###############################################################
#  Generated by:      Cadence Innovus 21.16-s078_1
#  OS:                Linux x86_64(Host ID r7cad-generic)
#  Generated on:      Sun Jun  2 17:44:32 2024
#  Design:            Pathtracer
#  Command:           write_lef_abstract -specifyTopLayer 6 -PGPinLayers {5 6} -noCutObs -stripePin results/Pathtracer.lef
###############################################################

VERSION 5.8 ;

BUSBITCHARS "[]" ;
DIVIDERCHAR "/" ;

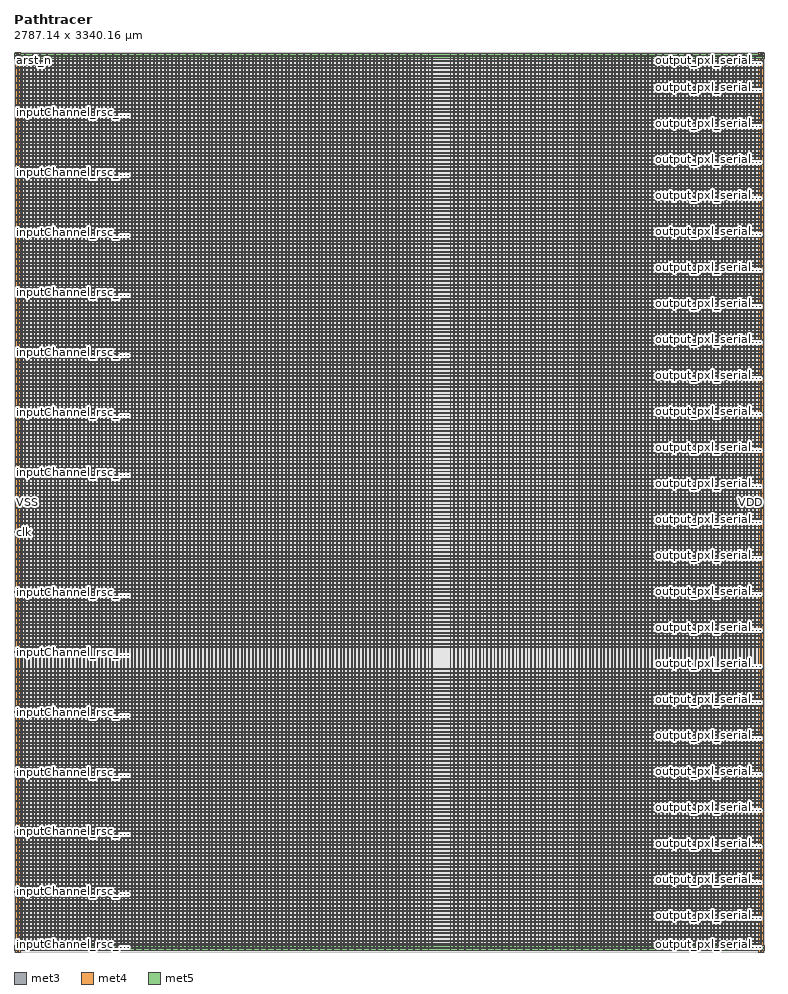
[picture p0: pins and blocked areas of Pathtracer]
MACRO Pathtracer
  CLASS BLOCK ;
  SIZE 2787.140000 BY 3340.160000 ;
  FOREIGN Pathtracer 0.000000 0.000000 ;
  ORIGIN 0 0 ;
  SYMMETRY X Y R90 ;
  PIN clk
    DIRECTION INPUT ;
    USE SIGNAL ;
    ANTENNAPARTIALMETALAREA 8.9964 LAYER met3  ;
    ANTENNAPARTIALMETALSIDEAREA 47.976 LAYER met3  ;
    ANTENNAMODEL OXIDE1 ;
    ANTENNAGATEAREA 0.576 LAYER met3  ;
    ANTENNAMAXAREACAR 17.1122 LAYER met3  ;
    ANTENNAMAXSIDEAREACAR 88.5634 LAYER met3  ;
    ANTENNAMAXCUTCAR 0.158681 LAYER via3  ;
    PORT
      LAYER met3 ;
        RECT 0.000000 1558.460000 0.800000 1558.760000 ;
    END
  END clk
  PIN arst_n
    DIRECTION INPUT ;
    USE SIGNAL ;
    ANTENNAPARTIALMETALAREA 8.8104 LAYER met3  ;
    ANTENNAPARTIALMETALSIDEAREA 46.984 LAYER met3  ;
    ANTENNAMODEL OXIDE1 ;
    ANTENNAGATEAREA 0.495 LAYER met3  ;
    ANTENNAMAXAREACAR 26.7883 LAYER met3  ;
    ANTENNAMAXSIDEAREACAR 138.764 LAYER met3  ;
    ANTENNAMAXCUTCAR 0.184646 LAYER via3  ;
    PORT
      LAYER met3 ;
        RECT 0.000000 3339.660000 0.800000 3339.960000 ;
    END
  END arst_n
  PIN inputChannel_rsc_dat[11]
    DIRECTION INPUT ;
    USE SIGNAL ;
    ANTENNAPARTIALMETALAREA 14.5426 LAYER met3  ;
    ANTENNAPARTIALMETALSIDEAREA 77.552 LAYER met3  ;
    ANTENNAPARTIALCUTAREA 0.04 LAYER via3  ;
    ANTENNAPARTIALMETALAREA 13.5838 LAYER met4  ;
    ANTENNAPARTIALMETALSIDEAREA 68.792 LAYER met4  ;
    ANTENNAPARTIALCUTAREA 0.64 LAYER via4  ;
    ANTENNADIFFAREA 0.4347 LAYER met5  ;
    ANTENNAPARTIALMETALAREA 85.36 LAYER met5  ;
    ANTENNAPARTIALMETALSIDEAREA 131.88 LAYER met5  ;
    ANTENNAMODEL OXIDE1 ;
    ANTENNAGATEAREA 0.2475 LAYER met5  ;
    ANTENNAMAXAREACAR 426.249 LAYER met5  ;
    ANTENNAMAXSIDEAREACAR 940.113 LAYER met5  ;
    PORT
      LAYER met3 ;
        RECT 0.000000 445.210000 0.800000 445.510000 ;
    END
  END inputChannel_rsc_dat[11]
  PIN inputChannel_rsc_dat[10]
    DIRECTION INPUT ;
    USE SIGNAL ;
    ANTENNAPARTIALMETALAREA 25.5874 LAYER met3  ;
    ANTENNAPARTIALMETALSIDEAREA 136.928 LAYER met3  ;
    ANTENNAPARTIALCUTAREA 0.04 LAYER via3  ;
    ANTENNAPARTIALMETALAREA 0.6516 LAYER met4  ;
    ANTENNAPARTIALMETALSIDEAREA 4.416 LAYER met4  ;
    ANTENNAMODEL OXIDE1 ;
    ANTENNAGATEAREA 0.2475 LAYER met4  ;
    ANTENNAMAXAREACAR 21.1174 LAYER met4  ;
    ANTENNAMAXSIDEAREACAR 109.038 LAYER met4  ;
    ANTENNAMAXCUTCAR 0.530909 LAYER via4  ;
    PORT
      LAYER met3 ;
        RECT 0.000000 667.860000 0.800000 668.160000 ;
    END
  END inputChannel_rsc_dat[10]
  PIN inputChannel_rsc_dat[9]
    DIRECTION INPUT ;
    USE SIGNAL ;
    ANTENNAPARTIALMETALAREA 22.3684 LAYER met3  ;
    ANTENNAPARTIALMETALSIDEAREA 119.76 LAYER met3  ;
    ANTENNAPARTIALCUTAREA 0.04 LAYER via3  ;
    ANTENNAPARTIALMETALAREA 0.6516 LAYER met4  ;
    ANTENNAPARTIALMETALSIDEAREA 4.416 LAYER met4  ;
    ANTENNAMODEL OXIDE1 ;
    ANTENNAGATEAREA 0.2475 LAYER met4  ;
    ANTENNAMAXAREACAR 29.9465 LAYER met4  ;
    ANTENNAMAXSIDEAREACAR 152.501 LAYER met4  ;
    ANTENNAMAXCUTCAR 0.530909 LAYER via4  ;
    PORT
      LAYER met3 ;
        RECT 0.000000 890.510000 0.800000 890.810000 ;
    END
  END inputChannel_rsc_dat[9]
  PIN inputChannel_rsc_dat[8]
    DIRECTION INPUT ;
    USE SIGNAL ;
    ANTENNAPARTIALMETALAREA 7.5334 LAYER met3  ;
    ANTENNAPARTIALMETALSIDEAREA 40.64 LAYER met3  ;
    ANTENNAPARTIALCUTAREA 0.04 LAYER via3  ;
    ANTENNAPARTIALMETALAREA 69.7006 LAYER met4  ;
    ANTENNAPARTIALMETALSIDEAREA 368.552 LAYER met4  ;
    ANTENNAPARTIALCUTAREA 0.64 LAYER via4  ;
    ANTENNADIFFAREA 0.4347 LAYER met5  ;
    ANTENNAPARTIALMETALAREA 112.96 LAYER met5  ;
    ANTENNAPARTIALMETALSIDEAREA 173.28 LAYER met5  ;
    ANTENNAMODEL OXIDE1 ;
    ANTENNAGATEAREA 0.2475 LAYER met5  ;
    ANTENNAMAXAREACAR 515.063 LAYER met5  ;
    ANTENNAMAXSIDEAREACAR 989.592 LAYER met5  ;
    PORT
      LAYER met3 ;
        RECT 0.000000 1113.160000 0.800000 1113.460000 ;
    END
  END inputChannel_rsc_dat[8]
  PIN inputChannel_rsc_dat[7]
    DIRECTION INPUT ;
    USE SIGNAL ;
    ANTENNAPARTIALMETALAREA 21.4024 LAYER met3  ;
    ANTENNAPARTIALMETALSIDEAREA 114.608 LAYER met3  ;
    ANTENNAPARTIALCUTAREA 0.04 LAYER via3  ;
    ANTENNAPARTIALMETALAREA 1.1766 LAYER met4  ;
    ANTENNAPARTIALMETALSIDEAREA 7.216 LAYER met4  ;
    ANTENNAMODEL OXIDE1 ;
    ANTENNAGATEAREA 0.2475 LAYER met4  ;
    ANTENNAMAXAREACAR 21.7735 LAYER met4  ;
    ANTENNAMAXSIDEAREACAR 112.036 LAYER met4  ;
    ANTENNAMAXCUTCAR 0.530909 LAYER via4  ;
    PORT
      LAYER met3 ;
        RECT 0.000000 1335.810000 0.800000 1336.110000 ;
    END
  END inputChannel_rsc_dat[7]
  PIN inputChannel_rsc_dat[6]
    DIRECTION INPUT ;
    USE SIGNAL ;
    ANTENNAPARTIALMETALAREA 14.1784 LAYER met3  ;
    ANTENNAPARTIALMETALSIDEAREA 76.08 LAYER met3  ;
    ANTENNAPARTIALCUTAREA 0.04 LAYER via3  ;
    ANTENNAPARTIALMETALAREA 0.6516 LAYER met4  ;
    ANTENNAPARTIALMETALSIDEAREA 4.416 LAYER met4  ;
    ANTENNAMODEL OXIDE1 ;
    ANTENNAGATEAREA 0.2475 LAYER met4  ;
    ANTENNAMAXAREACAR 50.3853 LAYER met4  ;
    ANTENNAMAXSIDEAREACAR 264.857 LAYER met4  ;
    ANTENNAMAXCUTCAR 0.530909 LAYER via4  ;
    PORT
      LAYER met3 ;
        RECT 0.000000 1781.110000 0.800000 1781.410000 ;
    END
  END inputChannel_rsc_dat[6]
  PIN inputChannel_rsc_dat[5]
    DIRECTION INPUT ;
    USE SIGNAL ;
    ANTENNAPARTIALMETALAREA 0.6954 LAYER met3  ;
    ANTENNAPARTIALMETALSIDEAREA 4.152 LAYER met3  ;
    ANTENNAPARTIALCUTAREA 0.04 LAYER via3  ;
    ANTENNAPARTIALMETALAREA 6.1578 LAYER met4  ;
    ANTENNAPARTIALMETALSIDEAREA 33.312 LAYER met4  ;
    ANTENNAMODEL OXIDE1 ;
    ANTENNAGATEAREA 0.1965 LAYER met4  ;
    ANTENNAMAXAREACAR 55.7527 LAYER met4  ;
    ANTENNAMAXSIDEAREACAR 290.656 LAYER met4  ;
    ANTENNAMAXCUTCAR 0.668702 LAYER via4  ;
    PORT
      LAYER met3 ;
        RECT 0.000000 2003.760000 0.800000 2004.060000 ;
    END
  END inputChannel_rsc_dat[5]
  PIN inputChannel_rsc_dat[4]
    DIRECTION INPUT ;
    USE SIGNAL ;
    ANTENNAPARTIALMETALAREA 6.3744 LAYER met3  ;
    ANTENNAPARTIALMETALSIDEAREA 33.992 LAYER met3  ;
    ANTENNAMODEL OXIDE1 ;
    ANTENNAGATEAREA 1.33 LAYER met3  ;
    ANTENNAMAXAREACAR 10.6479 LAYER met3  ;
    ANTENNAMAXSIDEAREACAR 54.0436 LAYER met3  ;
    ANTENNAMAXCUTCAR 0.0687218 LAYER via3  ;
    PORT
      LAYER met3 ;
        RECT 0.000000 2226.410000 0.800000 2226.710000 ;
    END
  END inputChannel_rsc_dat[4]
  PIN inputChannel_rsc_dat[3]
    DIRECTION INPUT ;
    USE SIGNAL ;
    ANTENNAPARTIALMETALAREA 8.3064 LAYER met3  ;
    ANTENNAPARTIALMETALSIDEAREA 44.296 LAYER met3  ;
    ANTENNAMODEL OXIDE1 ;
    ANTENNAGATEAREA 1.33 LAYER met3  ;
    ANTENNAMAXAREACAR 12.5679 LAYER met3  ;
    ANTENNAMAXSIDEAREACAR 64.1278 LAYER met3  ;
    ANTENNAMAXCUTCAR 0.0687218 LAYER via3  ;
    PORT
      LAYER met3 ;
        RECT 0.000000 2449.060000 0.800000 2449.360000 ;
    END
  END inputChannel_rsc_dat[3]
  PIN inputChannel_rsc_dat[2]
    DIRECTION INPUT ;
    USE SIGNAL ;
    ANTENNAPARTIALMETALAREA 0.467025 LAYER met3  ;
    ANTENNAPARTIALMETALSIDEAREA 2.464 LAYER met3  ;
    ANTENNAMODEL OXIDE1 ;
    ANTENNAGATEAREA 0.2475 LAYER met3  ;
    ANTENNAMAXAREACAR 98.466 LAYER met3  ;
    ANTENNAMAXSIDEAREACAR 490.628 LAYER met3  ;
    ANTENNAMAXCUTCAR 0.369293 LAYER via3  ;
    PORT
      LAYER met3 ;
        RECT 0.000000 2671.710000 0.800000 2672.010000 ;
    END
  END inputChannel_rsc_dat[2]
  PIN inputChannel_rsc_dat[1]
    DIRECTION INPUT ;
    USE SIGNAL ;
    ANTENNAPARTIALMETALAREA 0.4404 LAYER met3  ;
    ANTENNAPARTIALMETALSIDEAREA 2.344 LAYER met3  ;
    ANTENNAMODEL OXIDE1 ;
    ANTENNAGATEAREA 1.98 LAYER met3  ;
    ANTENNAMAXAREACAR 2.77518 LAYER met3  ;
    ANTENNAMAXSIDEAREACAR 12.3333 LAYER met3  ;
    ANTENNAMAXCUTCAR 0.0461616 LAYER via3  ;
    PORT
      LAYER met3 ;
        RECT 0.000000 2894.360000 0.800000 2894.660000 ;
    END
  END inputChannel_rsc_dat[1]
  PIN inputChannel_rsc_dat[0]
    DIRECTION INPUT ;
    USE SIGNAL ;
    ANTENNAPARTIALMETALAREA 0.1644 LAYER met3  ;
    ANTENNAPARTIALMETALSIDEAREA 0.872 LAYER met3  ;
    ANTENNAMODEL OXIDE1 ;
    ANTENNAGATEAREA 0.99 LAYER met3  ;
    ANTENNAMAXAREACAR 4.78626 LAYER met3  ;
    ANTENNAMAXSIDEAREACAR 22.098 LAYER met3  ;
    ANTENNAMAXCUTCAR 0.0923232 LAYER via3  ;
    PORT
      LAYER met3 ;
        RECT 0.000000 3117.010000 0.800000 3117.310000 ;
    END
  END inputChannel_rsc_dat[0]
  PIN inputChannel_rsc_vld
    DIRECTION INPUT ;
    USE SIGNAL ;
    ANTENNAPARTIALMETALAREA 4.1664 LAYER met3  ;
    ANTENNAPARTIALMETALSIDEAREA 22.216 LAYER met3  ;
    ANTENNAMODEL OXIDE1 ;
    ANTENNAGATEAREA 0.495 LAYER met3  ;
    ANTENNAMAXAREACAR 13.9792 LAYER met3  ;
    ANTENNAMAXSIDEAREACAR 70.4586 LAYER met3  ;
    ANTENNAMAXCUTCAR 0.184646 LAYER via3  ;
    PORT
      LAYER met3 ;
        RECT 0.000000 222.560000 0.800000 222.860000 ;
    END
  END inputChannel_rsc_vld
  PIN inputChannel_rsc_rdy
    DIRECTION OUTPUT ;
    USE SIGNAL ;
    ANTENNAPARTIALMETALAREA 104.747 LAYER met3  ;
    ANTENNAPARTIALMETALSIDEAREA 558.64 LAYER met3  ;
    ANTENNAPARTIALCUTAREA 0.04 LAYER via3  ;
    ANTENNAPARTIALMETALAREA 125.015 LAYER met4  ;
    ANTENNAPARTIALMETALSIDEAREA 664.504 LAYER met4  ;
    ANTENNAPARTIALCUTAREA 0.64 LAYER via4  ;
    ANTENNADIFFAREA 0.4455 LAYER met5  ;
    ANTENNAPARTIALMETALAREA 7.44 LAYER met5  ;
    ANTENNAPARTIALMETALSIDEAREA 15 LAYER met5  ;
    ANTENNAMODEL OXIDE1 ;
    ANTENNAGATEAREA 0.126 LAYER met5  ;
    ANTENNAMAXAREACAR 363.937 LAYER met5  ;
    ANTENNAMAXSIDEAREACAR 1706.82 LAYER met5  ;
    PORT
      LAYER met3 ;
        RECT 0.000000 0.520000 0.800000 0.820000 ;
    END
  END inputChannel_rsc_rdy
  PIN output_pxl_serial_rsc_dat[23]
    DIRECTION OUTPUT ;
    USE SIGNAL ;
    ANTENNADIFFAREA 0.4455 LAYER met3  ;
    ANTENNAPARTIALMETALAREA 0.2844 LAYER met3  ;
    ANTENNAPARTIALMETALSIDEAREA 1.992 LAYER met3  ;
    PORT
      LAYER met3 ;
        RECT 2786.340000 267.700000 2787.140000 268.000000 ;
    END
  END output_pxl_serial_rsc_dat[23]
  PIN output_pxl_serial_rsc_dat[22]
    DIRECTION OUTPUT ;
    USE SIGNAL ;
    ANTENNADIFFAREA 0.4455 LAYER met3  ;
    ANTENNAPARTIALMETALAREA 0.4224 LAYER met3  ;
    ANTENNAPARTIALMETALSIDEAREA 2.728 LAYER met3  ;
    PORT
      LAYER met3 ;
        RECT 2786.340000 401.290000 2787.140000 401.590000 ;
    END
  END output_pxl_serial_rsc_dat[22]
  PIN output_pxl_serial_rsc_dat[21]
    DIRECTION OUTPUT ;
    USE SIGNAL ;
    ANTENNAPARTIALMETALAREA 4.3786 LAYER met3  ;
    ANTENNAPARTIALMETALSIDEAREA 23.344 LAYER met3  ;
    ANTENNAPARTIALCUTAREA 0.04 LAYER via3  ;
    ANTENNADIFFAREA 0.4455 LAYER met4  ;
    ANTENNAPARTIALMETALAREA 18.0528 LAYER met4  ;
    ANTENNAPARTIALMETALSIDEAREA 96.752 LAYER met4  ;
    PORT
      LAYER met3 ;
        RECT 2786.340000 534.880000 2787.140000 535.180000 ;
    END
  END output_pxl_serial_rsc_dat[21]
  PIN output_pxl_serial_rsc_dat[20]
    DIRECTION OUTPUT ;
    USE SIGNAL ;
    ANTENNAPARTIALMETALAREA 0.2386 LAYER met3  ;
    ANTENNAPARTIALMETALSIDEAREA 1.264 LAYER met3  ;
    ANTENNAPARTIALCUTAREA 0.04 LAYER via3  ;
    ANTENNADIFFAREA 0.4455 LAYER met4  ;
    ANTENNAPARTIALMETALAREA 57.9468 LAYER met4  ;
    ANTENNAPARTIALMETALSIDEAREA 309.52 LAYER met4  ;
    PORT
      LAYER met3 ;
        RECT 2786.340000 668.470000 2787.140000 668.770000 ;
    END
  END output_pxl_serial_rsc_dat[20]
  PIN output_pxl_serial_rsc_dat[19]
    DIRECTION OUTPUT ;
    USE SIGNAL ;
    ANTENNADIFFAREA 0.4455 LAYER met3  ;
    ANTENNAPARTIALMETALAREA 2.3544 LAYER met3  ;
    ANTENNAPARTIALMETALSIDEAREA 13.032 LAYER met3  ;
    PORT
      LAYER met3 ;
        RECT 2786.340000 802.060000 2787.140000 802.360000 ;
    END
  END output_pxl_serial_rsc_dat[19]
  PIN output_pxl_serial_rsc_dat[18]
    DIRECTION OUTPUT ;
    USE SIGNAL ;
    ANTENNADIFFAREA 0.4455 LAYER met3  ;
    ANTENNAPARTIALMETALAREA 13.7892 LAYER met3  ;
    ANTENNAPARTIALMETALSIDEAREA 74.488 LAYER met3  ;
    PORT
      LAYER met3 ;
        RECT 2786.340000 935.650000 2787.140000 935.950000 ;
    END
  END output_pxl_serial_rsc_dat[18]
  PIN output_pxl_serial_rsc_dat[17]
    DIRECTION OUTPUT ;
    USE SIGNAL ;
    ANTENNADIFFAREA 0.4455 LAYER met3  ;
    ANTENNAPARTIALMETALAREA 1.6644 LAYER met3  ;
    ANTENNAPARTIALMETALSIDEAREA 9.352 LAYER met3  ;
    PORT
      LAYER met3 ;
        RECT 2786.340000 1069.240000 2787.140000 1069.540000 ;
    END
  END output_pxl_serial_rsc_dat[17]
  PIN output_pxl_serial_rsc_dat[16]
    DIRECTION OUTPUT ;
    USE SIGNAL ;
    ANTENNADIFFAREA 0.4455 LAYER met3  ;
    ANTENNAPARTIALMETALAREA 13.0992 LAYER met3  ;
    ANTENNAPARTIALMETALSIDEAREA 70.808 LAYER met3  ;
    PORT
      LAYER met3 ;
        RECT 2786.340000 1202.830000 2787.140000 1203.130000 ;
    END
  END output_pxl_serial_rsc_dat[16]
  PIN output_pxl_serial_rsc_dat[15]
    DIRECTION OUTPUT ;
    USE SIGNAL ;
    ANTENNADIFFAREA 0.4455 LAYER met3  ;
    ANTENNAPARTIALMETALAREA 1.5264 LAYER met3  ;
    ANTENNAPARTIALMETALSIDEAREA 8.616 LAYER met3  ;
    PORT
      LAYER met3 ;
        RECT 2786.340000 1336.420000 2787.140000 1336.720000 ;
    END
  END output_pxl_serial_rsc_dat[15]
  PIN output_pxl_serial_rsc_dat[14]
    DIRECTION OUTPUT ;
    USE SIGNAL ;
    ANTENNADIFFAREA 0.4455 LAYER met3  ;
    ANTENNAPARTIALMETALAREA 0.5604 LAYER met3  ;
    ANTENNAPARTIALMETALSIDEAREA 3.464 LAYER met3  ;
    PORT
      LAYER met3 ;
        RECT 2786.340000 1470.010000 2787.140000 1470.310000 ;
    END
  END output_pxl_serial_rsc_dat[14]
  PIN output_pxl_serial_rsc_dat[13]
    DIRECTION OUTPUT ;
    USE SIGNAL ;
    ANTENNADIFFAREA 0.4455 LAYER met3  ;
    ANTENNAPARTIALMETALAREA 0.5604 LAYER met3  ;
    ANTENNAPARTIALMETALSIDEAREA 3.464 LAYER met3  ;
    PORT
      LAYER met3 ;
        RECT 2786.340000 1603.600000 2787.140000 1603.900000 ;
    END
  END output_pxl_serial_rsc_dat[13]
  PIN output_pxl_serial_rsc_dat[12]
    DIRECTION OUTPUT ;
    USE SIGNAL ;
    ANTENNADIFFAREA 0.43675 LAYER met3  ;
    ANTENNAPARTIALMETALAREA 0.3024 LAYER met3  ;
    ANTENNAPARTIALMETALSIDEAREA 1.608 LAYER met3  ;
    PORT
      LAYER met3 ;
        RECT 2786.340000 1737.190000 2787.140000 1737.490000 ;
    END
  END output_pxl_serial_rsc_dat[12]
  PIN output_pxl_serial_rsc_dat[11]
    DIRECTION OUTPUT ;
    USE SIGNAL ;
    ANTENNADIFFAREA 0.43675 LAYER met3  ;
    ANTENNAPARTIALMETALAREA 0.6492 LAYER met3  ;
    ANTENNAPARTIALMETALSIDEAREA 3.928 LAYER met3  ;
    PORT
      LAYER met3 ;
        RECT 2786.340000 1870.780000 2787.140000 1871.080000 ;
    END
  END output_pxl_serial_rsc_dat[11]
  PIN output_pxl_serial_rsc_dat[10]
    DIRECTION OUTPUT ;
    USE SIGNAL ;
    ANTENNADIFFAREA 0.43675 LAYER met3  ;
    ANTENNAPARTIALMETALAREA 5.9604 LAYER met3  ;
    ANTENNAPARTIALMETALSIDEAREA 31.784 LAYER met3  ;
    PORT
      LAYER met3 ;
        RECT 2786.340000 2004.370000 2787.140000 2004.670000 ;
    END
  END output_pxl_serial_rsc_dat[10]
  PIN output_pxl_serial_rsc_dat[9]
    DIRECTION OUTPUT ;
    USE SIGNAL ;
    ANTENNADIFFAREA 0.43675 LAYER met3  ;
    ANTENNAPARTIALMETALAREA 0.7164 LAYER met3  ;
    ANTENNAPARTIALMETALSIDEAREA 3.816 LAYER met3  ;
    PORT
      LAYER met3 ;
        RECT 2786.340000 2137.960000 2787.140000 2138.260000 ;
    END
  END output_pxl_serial_rsc_dat[9]
  PIN output_pxl_serial_rsc_dat[8]
    DIRECTION OUTPUT ;
    USE SIGNAL ;
    ANTENNADIFFAREA 0.714 LAYER met3  ;
    ANTENNAPARTIALMETALAREA 0.7164 LAYER met3  ;
    ANTENNAPARTIALMETALSIDEAREA 3.816 LAYER met3  ;
    PORT
      LAYER met3 ;
        RECT 2786.340000 2271.550000 2787.140000 2271.850000 ;
    END
  END output_pxl_serial_rsc_dat[8]
  PIN output_pxl_serial_rsc_dat[7]
    DIRECTION OUTPUT ;
    USE SIGNAL ;
    ANTENNADIFFAREA 0.714 LAYER met3  ;
    ANTENNAPARTIALMETALAREA 0.4404 LAYER met3  ;
    ANTENNAPARTIALMETALSIDEAREA 2.344 LAYER met3  ;
    PORT
      LAYER met3 ;
        RECT 2786.340000 2405.140000 2787.140000 2405.440000 ;
    END
  END output_pxl_serial_rsc_dat[7]
  PIN output_pxl_serial_rsc_dat[6]
    DIRECTION OUTPUT ;
    USE SIGNAL ;
    ANTENNADIFFAREA 0.714 LAYER met3  ;
    ANTENNAPARTIALMETALAREA 0.8544 LAYER met3  ;
    ANTENNAPARTIALMETALSIDEAREA 4.552 LAYER met3  ;
    PORT
      LAYER met3 ;
        RECT 2786.340000 2538.730000 2787.140000 2539.030000 ;
    END
  END output_pxl_serial_rsc_dat[6]
  PIN output_pxl_serial_rsc_dat[5]
    DIRECTION OUTPUT ;
    USE SIGNAL ;
    ANTENNADIFFAREA 0.714 LAYER met3  ;
    ANTENNAPARTIALMETALAREA 0.1644 LAYER met3  ;
    ANTENNAPARTIALMETALSIDEAREA 0.872 LAYER met3  ;
    PORT
      LAYER met3 ;
        RECT 2786.340000 2672.320000 2787.140000 2672.620000 ;
    END
  END output_pxl_serial_rsc_dat[5]
  PIN output_pxl_serial_rsc_dat[4]
    DIRECTION OUTPUT ;
    USE SIGNAL ;
    ANTENNADIFFAREA 0.43675 LAYER met3  ;
    ANTENNAPARTIALMETALAREA 0.8544 LAYER met3  ;
    ANTENNAPARTIALMETALSIDEAREA 4.552 LAYER met3  ;
    PORT
      LAYER met3 ;
        RECT 2786.340000 2805.910000 2787.140000 2806.210000 ;
    END
  END output_pxl_serial_rsc_dat[4]
  PIN output_pxl_serial_rsc_dat[3]
    DIRECTION OUTPUT ;
    USE SIGNAL ;
    ANTENNADIFFAREA 0.714 LAYER met3  ;
    ANTENNAPARTIALMETALAREA 0.1644 LAYER met3  ;
    ANTENNAPARTIALMETALSIDEAREA 0.872 LAYER met3  ;
    PORT
      LAYER met3 ;
        RECT 2786.340000 2939.500000 2787.140000 2939.800000 ;
    END
  END output_pxl_serial_rsc_dat[3]
  PIN output_pxl_serial_rsc_dat[2]
    DIRECTION OUTPUT ;
    USE SIGNAL ;
    ANTENNADIFFAREA 0.714 LAYER met3  ;
    ANTENNAPARTIALMETALAREA 0.9924 LAYER met3  ;
    ANTENNAPARTIALMETALSIDEAREA 5.288 LAYER met3  ;
    PORT
      LAYER met3 ;
        RECT 2786.340000 3073.090000 2787.140000 3073.390000 ;
    END
  END output_pxl_serial_rsc_dat[2]
  PIN output_pxl_serial_rsc_dat[1]
    DIRECTION OUTPUT ;
    USE SIGNAL ;
    ANTENNADIFFAREA 0.714 LAYER met3  ;
    ANTENNAPARTIALMETALAREA 1.9584 LAYER met3  ;
    ANTENNAPARTIALMETALSIDEAREA 10.44 LAYER met3  ;
    PORT
      LAYER met3 ;
        RECT 2786.340000 3206.680000 2787.140000 3206.980000 ;
    END
  END output_pxl_serial_rsc_dat[1]
  PIN output_pxl_serial_rsc_dat[0]
    DIRECTION OUTPUT ;
    USE SIGNAL ;
    ANTENNADIFFAREA 0.43675 LAYER met3  ;
    ANTENNAPARTIALMETALAREA 0.8064 LAYER met3  ;
    ANTENNAPARTIALMETALSIDEAREA 4.296 LAYER met3  ;
    PORT
      LAYER met3 ;
        RECT 2786.340000 3339.660000 2787.140000 3339.960000 ;
    END
  END output_pxl_serial_rsc_dat[0]
  PIN output_pxl_serial_rsc_vld
    DIRECTION OUTPUT ;
    USE SIGNAL ;
    ANTENNADIFFAREA 0.4355 LAYER met3  ;
    ANTENNAPARTIALMETALAREA 7.7364 LAYER met3  ;
    ANTENNAPARTIALMETALSIDEAREA 41.736 LAYER met3  ;
    ANTENNAMODEL OXIDE1 ;
    ANTENNAGATEAREA 0.126 LAYER met3  ;
    ANTENNAMAXAREACAR 226.856 LAYER met3  ;
    ANTENNAMAXSIDEAREACAR 1145.98 LAYER met3  ;
    ANTENNAMAXCUTCAR 0.903968 LAYER via3  ;
    PORT
      LAYER met3 ;
        RECT 2786.340000 134.110000 2787.140000 134.410000 ;
    END
  END output_pxl_serial_rsc_vld
  PIN output_pxl_serial_rsc_rdy
    DIRECTION INPUT ;
    USE SIGNAL ;
    ANTENNAPARTIALMETALAREA 1.662 LAYER met3  ;
    ANTENNAPARTIALMETALSIDEAREA 10.28 LAYER met3  ;
    ANTENNAMODEL OXIDE1 ;
    ANTENNAGATEAREA 0.126 LAYER met3  ;
    ANTENNAMAXAREACAR 66.9472 LAYER met3  ;
    ANTENNAMAXSIDEAREACAR 342.766 LAYER met3  ;
    ANTENNAMAXCUTCAR 0.725397 LAYER via3  ;
    PORT
      LAYER met3 ;
        RECT 2786.340000 0.520000 2787.140000 0.820000 ;
    END
  END output_pxl_serial_rsc_rdy
  PIN VSS
    DIRECTION INOUT ;
    USE GROUND ;
    PORT
      LAYER met4 ;
        RECT 2774.480000 3332.000000 2782.640000 3340.160000 ;
    END
    PORT
      LAYER met4 ;
        RECT 2774.480000 0.000000 2782.640000 8.160000 ;
    END
    PORT
      LAYER met4 ;
        RECT 4.500000 3332.000000 12.660000 3340.160000 ;
    END
    PORT
      LAYER met4 ;
        RECT 4.500000 0.000000 12.660000 8.160000 ;
    END
    PORT
      LAYER met5 ;
        RECT 2778.980000 3327.920000 2787.140000 3336.080000 ;
    END
    PORT
      LAYER met5 ;
        RECT 0.000000 3327.920000 8.160000 3336.080000 ;
    END
    PORT
      LAYER met5 ;
        RECT 2778.980000 4.080000 2787.140000 12.240000 ;
    END
    PORT
      LAYER met5 ;
        RECT 0.000000 4.080000 8.160000 12.240000 ;
    END

# P/G power stripe data as pin
    PORT
      LAYER met4 ;
        RECT 40.800000 4.080000 44.160000 3336.080000 ;
        RECT 2774.480000 0.000000 2782.640000 3340.160000 ;
        RECT 4.500000 0.000000 12.660000 3340.160000 ;
        RECT 1618.400000 4.080000 1621.760000 3336.080000 ;
        RECT 68.000000 4.080000 71.360000 3336.080000 ;
        RECT 95.200000 4.080000 98.560000 3336.080000 ;
        RECT 122.400000 4.080000 125.760000 3336.080000 ;
        RECT 149.600000 4.080000 152.960000 3336.080000 ;
        RECT 176.800000 4.080000 180.160000 3336.080000 ;
        RECT 204.000000 4.080000 207.360000 3336.080000 ;
        RECT 231.200000 4.080000 234.560000 3336.080000 ;
        RECT 258.400000 4.080000 261.760000 3336.080000 ;
        RECT 285.600000 4.080000 288.960000 3336.080000 ;
        RECT 312.800000 4.080000 316.160000 3336.080000 ;
        RECT 340.000000 4.080000 343.360000 3336.080000 ;
        RECT 367.200000 4.080000 370.560000 3336.080000 ;
        RECT 394.400000 4.080000 397.760000 3336.080000 ;
        RECT 421.600000 4.080000 424.960000 3336.080000 ;
        RECT 448.800000 4.080000 452.160000 3336.080000 ;
        RECT 476.000000 4.080000 479.360000 3336.080000 ;
        RECT 503.200000 4.080000 506.560000 3336.080000 ;
        RECT 530.400000 4.080000 533.760000 3336.080000 ;
        RECT 557.600000 4.080000 560.960000 3336.080000 ;
        RECT 584.800000 4.080000 588.160000 3336.080000 ;
        RECT 612.000000 4.080000 615.360000 3336.080000 ;
        RECT 639.200000 4.080000 642.560000 3336.080000 ;
        RECT 666.400000 4.080000 669.760000 3336.080000 ;
        RECT 693.600000 4.080000 696.960000 3336.080000 ;
        RECT 720.800000 4.080000 724.160000 3336.080000 ;
        RECT 748.000000 4.080000 751.360000 3336.080000 ;
        RECT 775.200000 4.080000 778.560000 3336.080000 ;
        RECT 802.400000 4.080000 805.760000 3336.080000 ;
        RECT 829.600000 4.080000 832.960000 3336.080000 ;
        RECT 856.800000 4.080000 860.160000 3336.080000 ;
        RECT 884.000000 4.080000 887.360000 3336.080000 ;
        RECT 911.200000 4.080000 914.560000 3336.080000 ;
        RECT 938.400000 4.080000 941.760000 3336.080000 ;
        RECT 965.600000 4.080000 968.960000 3336.080000 ;
        RECT 992.800000 4.080000 996.160000 3336.080000 ;
        RECT 1020.000000 4.080000 1023.360000 3336.080000 ;
        RECT 1047.200000 4.080000 1050.560000 3336.080000 ;
        RECT 1074.400000 4.080000 1077.760000 3336.080000 ;
        RECT 1101.600000 4.080000 1104.960000 3336.080000 ;
        RECT 1128.800000 4.080000 1132.160000 3336.080000 ;
        RECT 1156.000000 4.080000 1159.360000 3336.080000 ;
        RECT 1183.200000 4.080000 1186.560000 3336.080000 ;
        RECT 1210.400000 4.080000 1213.760000 3336.080000 ;
        RECT 1237.600000 4.080000 1240.960000 3336.080000 ;
        RECT 1264.800000 4.080000 1268.160000 3336.080000 ;
        RECT 1292.000000 4.080000 1295.360000 3336.080000 ;
        RECT 1319.200000 4.080000 1322.560000 3336.080000 ;
        RECT 1346.400000 4.080000 1349.760000 3336.080000 ;
        RECT 1373.600000 4.080000 1376.960000 3336.080000 ;
        RECT 1400.800000 4.080000 1404.160000 3336.080000 ;
        RECT 1428.000000 4.080000 1431.360000 3336.080000 ;
        RECT 1455.200000 4.080000 1458.560000 3336.080000 ;
        RECT 1482.400000 4.080000 1485.760000 3336.080000 ;
        RECT 1509.600000 4.080000 1512.960000 3336.080000 ;
        RECT 1536.800000 4.080000 1540.160000 3336.080000 ;
        RECT 1645.600000 4.080000 1648.960000 3336.080000 ;
        RECT 1672.800000 4.080000 1676.160000 3336.080000 ;
        RECT 1700.000000 4.080000 1703.360000 3336.080000 ;
        RECT 1727.200000 4.080000 1730.560000 3336.080000 ;
        RECT 1754.400000 4.080000 1757.760000 3336.080000 ;
        RECT 1781.600000 4.080000 1784.960000 3336.080000 ;
        RECT 1808.800000 4.080000 1812.160000 3336.080000 ;
        RECT 1836.000000 4.080000 1839.360000 3336.080000 ;
        RECT 1863.200000 4.080000 1866.560000 3336.080000 ;
        RECT 1890.400000 4.080000 1893.760000 3336.080000 ;
        RECT 1917.600000 4.080000 1920.960000 3336.080000 ;
        RECT 1944.800000 4.080000 1948.160000 3336.080000 ;
        RECT 1972.000000 4.080000 1975.360000 3336.080000 ;
        RECT 1999.200000 4.080000 2002.560000 3336.080000 ;
        RECT 2026.400000 4.080000 2029.760000 3336.080000 ;
        RECT 2053.600000 4.080000 2056.960000 3336.080000 ;
        RECT 2080.800000 4.080000 2084.160000 3336.080000 ;
        RECT 2108.000000 4.080000 2111.360000 3336.080000 ;
        RECT 2135.200000 4.080000 2138.560000 3336.080000 ;
        RECT 2162.400000 4.080000 2165.760000 3336.080000 ;
        RECT 2189.600000 4.080000 2192.960000 3336.080000 ;
        RECT 2216.800000 4.080000 2220.160000 3336.080000 ;
        RECT 2244.000000 4.080000 2247.360000 3336.080000 ;
        RECT 2271.200000 4.080000 2274.560000 3336.080000 ;
        RECT 2298.400000 4.080000 2301.760000 3336.080000 ;
        RECT 2325.600000 4.080000 2328.960000 3336.080000 ;
        RECT 2352.800000 4.080000 2356.160000 3336.080000 ;
        RECT 2380.000000 4.080000 2383.360000 3336.080000 ;
        RECT 2407.200000 4.080000 2410.560000 3336.080000 ;
        RECT 2434.400000 4.080000 2437.760000 3336.080000 ;
        RECT 2461.600000 4.080000 2464.960000 3336.080000 ;
        RECT 2488.800000 4.080000 2492.160000 3336.080000 ;
        RECT 2516.000000 4.080000 2519.360000 3336.080000 ;
        RECT 2543.200000 4.080000 2546.560000 3336.080000 ;
        RECT 2570.400000 4.080000 2573.760000 3336.080000 ;
        RECT 2597.600000 4.080000 2600.960000 3336.080000 ;
        RECT 2624.800000 4.080000 2628.160000 3336.080000 ;
        RECT 2652.000000 4.080000 2655.360000 3336.080000 ;
        RECT 2679.200000 4.080000 2682.560000 3336.080000 ;
        RECT 2706.400000 4.080000 2709.760000 3336.080000 ;
        RECT 2733.600000 4.080000 2736.960000 3336.080000 ;
      LAYER met5 ;
        RECT 0.000000 4.080000 2787.140000 12.240000 ;
        RECT 4.500000 40.800000 2782.640000 44.160000 ;
        RECT 0.000000 3327.920000 2787.140000 3336.080000 ;
        RECT 4.500000 1128.800000 2782.640000 1132.160000 ;
        RECT 4.500000 1156.000000 2782.640000 1159.360000 ;
        RECT 4.500000 1183.200000 2782.640000 1186.560000 ;
        RECT 4.500000 1210.400000 2782.640000 1213.760000 ;
        RECT 4.500000 1237.600000 2782.640000 1240.960000 ;
        RECT 4.500000 1264.800000 2782.640000 1268.160000 ;
        RECT 4.500000 1292.000000 2782.640000 1295.360000 ;
        RECT 4.500000 1319.200000 2782.640000 1322.560000 ;
        RECT 4.500000 1346.400000 2782.640000 1349.760000 ;
        RECT 4.500000 1373.600000 2782.640000 1376.960000 ;
        RECT 4.500000 1400.800000 2782.640000 1404.160000 ;
        RECT 4.500000 1428.000000 2782.640000 1431.360000 ;
        RECT 4.500000 1455.200000 2782.640000 1458.560000 ;
        RECT 4.500000 1482.400000 2782.640000 1485.760000 ;
        RECT 4.500000 1509.600000 2782.640000 1512.960000 ;
        RECT 4.500000 1536.800000 2782.640000 1540.160000 ;
        RECT 4.500000 1564.000000 2782.640000 1567.360000 ;
        RECT 4.500000 1591.200000 2782.640000 1594.560000 ;
        RECT 4.500000 1618.400000 2782.640000 1621.760000 ;
        RECT 4.500000 1645.600000 2782.640000 1648.960000 ;
        RECT 4.500000 1672.800000 2782.640000 1676.160000 ;
        RECT 4.500000 1700.000000 2782.640000 1703.360000 ;
        RECT 4.500000 1727.200000 2782.640000 1730.560000 ;
        RECT 4.500000 1754.400000 2782.640000 1757.760000 ;
        RECT 4.500000 1781.600000 2782.640000 1784.960000 ;
        RECT 4.500000 1808.800000 2782.640000 1812.160000 ;
        RECT 4.500000 1836.000000 2782.640000 1839.360000 ;
        RECT 4.500000 1863.200000 2782.640000 1866.560000 ;
        RECT 4.500000 1890.400000 2782.640000 1893.760000 ;
        RECT 4.500000 1917.600000 2782.640000 1920.960000 ;
        RECT 4.500000 1944.800000 2782.640000 1948.160000 ;
        RECT 4.500000 1972.000000 2782.640000 1975.360000 ;
        RECT 4.500000 1999.200000 2782.640000 2002.560000 ;
        RECT 4.500000 2026.400000 2782.640000 2029.760000 ;
        RECT 4.500000 2053.600000 2782.640000 2056.960000 ;
        RECT 4.500000 2080.800000 2782.640000 2084.160000 ;
        RECT 4.500000 2108.000000 2782.640000 2111.360000 ;
        RECT 4.500000 2135.200000 2782.640000 2138.560000 ;
        RECT 4.500000 2162.400000 2782.640000 2165.760000 ;
        RECT 4.500000 2189.600000 2782.640000 2192.960000 ;
        RECT 4.500000 2216.800000 2782.640000 2220.160000 ;
        RECT 4.500000 2244.000000 2782.640000 2247.360000 ;
        RECT 4.500000 2271.200000 2782.640000 2274.560000 ;
        RECT 4.500000 2298.400000 2782.640000 2301.760000 ;
        RECT 4.500000 2325.600000 2782.640000 2328.960000 ;
        RECT 4.500000 2352.800000 2782.640000 2356.160000 ;
        RECT 4.500000 2380.000000 2782.640000 2383.360000 ;
        RECT 4.500000 2407.200000 2782.640000 2410.560000 ;
        RECT 4.500000 2434.400000 2782.640000 2437.760000 ;
        RECT 4.500000 2461.600000 2782.640000 2464.960000 ;
        RECT 4.500000 2488.800000 2782.640000 2492.160000 ;
        RECT 4.500000 2516.000000 2782.640000 2519.360000 ;
        RECT 4.500000 2543.200000 2782.640000 2546.560000 ;
        RECT 4.500000 2570.400000 2782.640000 2573.760000 ;
        RECT 4.500000 2597.600000 2782.640000 2600.960000 ;
        RECT 4.500000 2624.800000 2782.640000 2628.160000 ;
        RECT 4.500000 2652.000000 2782.640000 2655.360000 ;
        RECT 4.500000 2679.200000 2782.640000 2682.560000 ;
        RECT 4.500000 2706.400000 2782.640000 2709.760000 ;
        RECT 4.500000 2733.600000 2782.640000 2736.960000 ;
        RECT 4.500000 2760.800000 2782.640000 2764.160000 ;
        RECT 4.500000 2788.000000 2782.640000 2791.360000 ;
        RECT 4.500000 2815.200000 2782.640000 2818.560000 ;
        RECT 4.500000 2842.400000 2782.640000 2845.760000 ;
        RECT 4.500000 2869.600000 2782.640000 2872.960000 ;
        RECT 4.500000 2896.800000 2782.640000 2900.160000 ;
        RECT 4.500000 2924.000000 2782.640000 2927.360000 ;
        RECT 4.500000 2951.200000 2782.640000 2954.560000 ;
        RECT 4.500000 2978.400000 2782.640000 2981.760000 ;
        RECT 4.500000 3005.600000 2782.640000 3008.960000 ;
        RECT 4.500000 3032.800000 2782.640000 3036.160000 ;
        RECT 4.500000 3060.000000 2782.640000 3063.360000 ;
        RECT 4.500000 3087.200000 2782.640000 3090.560000 ;
        RECT 4.500000 3114.400000 2782.640000 3117.760000 ;
        RECT 4.500000 3141.600000 2782.640000 3144.960000 ;
        RECT 4.500000 3168.800000 2782.640000 3172.160000 ;
        RECT 4.500000 3196.000000 2782.640000 3199.360000 ;
        RECT 4.500000 3223.200000 2782.640000 3226.560000 ;
        RECT 4.500000 3250.400000 2782.640000 3253.760000 ;
        RECT 4.500000 3277.600000 2782.640000 3280.960000 ;
        RECT 4.500000 3304.800000 2782.640000 3308.160000 ;
        RECT 4.500000 68.000000 2782.640000 71.360000 ;
        RECT 4.500000 95.200000 2782.640000 98.560000 ;
        RECT 4.500000 122.400000 2782.640000 125.760000 ;
        RECT 4.500000 149.600000 2782.640000 152.960000 ;
        RECT 4.500000 176.800000 2782.640000 180.160000 ;
        RECT 4.500000 204.000000 2782.640000 207.360000 ;
        RECT 4.500000 231.200000 2782.640000 234.560000 ;
        RECT 4.500000 258.400000 2782.640000 261.760000 ;
        RECT 4.500000 285.600000 2782.640000 288.960000 ;
        RECT 4.500000 312.800000 2782.640000 316.160000 ;
        RECT 4.500000 340.000000 2782.640000 343.360000 ;
        RECT 4.500000 367.200000 2782.640000 370.560000 ;
        RECT 4.500000 394.400000 2782.640000 397.760000 ;
        RECT 4.500000 421.600000 2782.640000 424.960000 ;
        RECT 4.500000 448.800000 2782.640000 452.160000 ;
        RECT 4.500000 476.000000 2782.640000 479.360000 ;
        RECT 4.500000 503.200000 2782.640000 506.560000 ;
        RECT 4.500000 530.400000 2782.640000 533.760000 ;
        RECT 4.500000 557.600000 2782.640000 560.960000 ;
        RECT 4.500000 584.800000 2782.640000 588.160000 ;
        RECT 4.500000 612.000000 2782.640000 615.360000 ;
        RECT 4.500000 639.200000 2782.640000 642.560000 ;
        RECT 4.500000 666.400000 2782.640000 669.760000 ;
        RECT 4.500000 693.600000 2782.640000 696.960000 ;
        RECT 4.500000 720.800000 2782.640000 724.160000 ;
        RECT 4.500000 748.000000 2782.640000 751.360000 ;
        RECT 4.500000 775.200000 2782.640000 778.560000 ;
        RECT 4.500000 802.400000 2782.640000 805.760000 ;
        RECT 4.500000 829.600000 2782.640000 832.960000 ;
        RECT 4.500000 856.800000 2782.640000 860.160000 ;
        RECT 4.500000 884.000000 2782.640000 887.360000 ;
        RECT 4.500000 911.200000 2782.640000 914.560000 ;
        RECT 4.500000 938.400000 2782.640000 941.760000 ;
        RECT 4.500000 965.600000 2782.640000 968.960000 ;
        RECT 4.500000 992.800000 2782.640000 996.160000 ;
        RECT 4.500000 1020.000000 2782.640000 1023.360000 ;
        RECT 4.500000 1047.200000 2782.640000 1050.560000 ;
    END
# end of P/G power stripe data as pin

  END VSS
  PIN VDD
    DIRECTION INOUT ;
    USE POWER ;
    PORT
      LAYER met4 ;
        RECT 2762.240000 3332.000000 2770.400000 3340.160000 ;
    END
    PORT
      LAYER met4 ;
        RECT 2762.240000 0.000000 2770.400000 8.160000 ;
    END
    PORT
      LAYER met4 ;
        RECT 16.740000 3332.000000 24.900000 3340.160000 ;
    END
    PORT
      LAYER met4 ;
        RECT 16.740000 0.000000 24.900000 8.160000 ;
    END
    PORT
      LAYER met5 ;
        RECT 2778.980000 3315.680000 2787.140000 3323.840000 ;
    END
    PORT
      LAYER met5 ;
        RECT 0.000000 3315.680000 8.160000 3323.840000 ;
    END
    PORT
      LAYER met5 ;
        RECT 2778.980000 16.320000 2787.140000 24.480000 ;
    END
    PORT
      LAYER met5 ;
        RECT 0.000000 16.320000 8.160000 24.480000 ;
    END

# P/G power stripe data as pin
    PORT
      LAYER met4 ;
        RECT 27.200000 16.320000 30.560000 3323.840000 ;
        RECT 2762.240000 0.000000 2770.400000 3340.160000 ;
        RECT 16.740000 0.000000 24.900000 3340.160000 ;
        RECT 1632.000000 16.320000 1635.360000 3323.840000 ;
        RECT 54.400000 16.320000 57.760000 3323.840000 ;
        RECT 81.600000 16.320000 84.960000 3323.840000 ;
        RECT 108.800000 16.320000 112.160000 3323.840000 ;
        RECT 136.000000 16.320000 139.360000 3323.840000 ;
        RECT 163.200000 16.320000 166.560000 3323.840000 ;
        RECT 190.400000 16.320000 193.760000 3323.840000 ;
        RECT 217.600000 16.320000 220.960000 3323.840000 ;
        RECT 244.800000 16.320000 248.160000 3323.840000 ;
        RECT 272.000000 16.320000 275.360000 3323.840000 ;
        RECT 299.200000 16.320000 302.560000 3323.840000 ;
        RECT 326.400000 16.320000 329.760000 3323.840000 ;
        RECT 353.600000 16.320000 356.960000 3323.840000 ;
        RECT 380.800000 16.320000 384.160000 3323.840000 ;
        RECT 408.000000 16.320000 411.360000 3323.840000 ;
        RECT 435.200000 16.320000 438.560000 3323.840000 ;
        RECT 462.400000 16.320000 465.760000 3323.840000 ;
        RECT 489.600000 16.320000 492.960000 3323.840000 ;
        RECT 516.800000 16.320000 520.160000 3323.840000 ;
        RECT 544.000000 16.320000 547.360000 3323.840000 ;
        RECT 571.200000 16.320000 574.560000 3323.840000 ;
        RECT 598.400000 16.320000 601.760000 3323.840000 ;
        RECT 625.600000 16.320000 628.960000 3323.840000 ;
        RECT 652.800000 16.320000 656.160000 3323.840000 ;
        RECT 680.000000 16.320000 683.360000 3323.840000 ;
        RECT 707.200000 16.320000 710.560000 3323.840000 ;
        RECT 734.400000 16.320000 737.760000 3323.840000 ;
        RECT 761.600000 16.320000 764.960000 3323.840000 ;
        RECT 788.800000 16.320000 792.160000 3323.840000 ;
        RECT 816.000000 16.320000 819.360000 3323.840000 ;
        RECT 843.200000 16.320000 846.560000 3323.840000 ;
        RECT 870.400000 16.320000 873.760000 3323.840000 ;
        RECT 897.600000 16.320000 900.960000 3323.840000 ;
        RECT 924.800000 16.320000 928.160000 3323.840000 ;
        RECT 952.000000 16.320000 955.360000 3323.840000 ;
        RECT 979.200000 16.320000 982.560000 3323.840000 ;
        RECT 1006.400000 16.320000 1009.760000 3323.840000 ;
        RECT 1033.600000 16.320000 1036.960000 3323.840000 ;
        RECT 1060.800000 16.320000 1064.160000 3323.840000 ;
        RECT 1088.000000 16.320000 1091.360000 3323.840000 ;
        RECT 1115.200000 16.320000 1118.560000 3323.840000 ;
        RECT 1142.400000 16.320000 1145.760000 3323.840000 ;
        RECT 1169.600000 16.320000 1172.960000 3323.840000 ;
        RECT 1196.800000 16.320000 1200.160000 3323.840000 ;
        RECT 1224.000000 16.320000 1227.360000 3323.840000 ;
        RECT 1251.200000 16.320000 1254.560000 3323.840000 ;
        RECT 1278.400000 16.320000 1281.760000 3323.840000 ;
        RECT 1305.600000 16.320000 1308.960000 3323.840000 ;
        RECT 1332.800000 16.320000 1336.160000 3323.840000 ;
        RECT 1360.000000 16.320000 1363.360000 3323.840000 ;
        RECT 1387.200000 16.320000 1390.560000 3323.840000 ;
        RECT 1414.400000 16.320000 1417.760000 3323.840000 ;
        RECT 1441.600000 16.320000 1444.960000 3323.840000 ;
        RECT 1468.800000 16.320000 1472.160000 3323.840000 ;
        RECT 1496.000000 16.320000 1499.360000 3323.840000 ;
        RECT 1523.200000 16.320000 1526.560000 3323.840000 ;
        RECT 1550.400000 16.320000 1553.760000 3323.840000 ;
        RECT 1659.200000 16.320000 1662.560000 3323.840000 ;
        RECT 1686.400000 16.320000 1689.760000 3323.840000 ;
        RECT 1713.600000 16.320000 1716.960000 3323.840000 ;
        RECT 1740.800000 16.320000 1744.160000 3323.840000 ;
        RECT 1768.000000 16.320000 1771.360000 3323.840000 ;
        RECT 1795.200000 16.320000 1798.560000 3323.840000 ;
        RECT 1822.400000 16.320000 1825.760000 3323.840000 ;
        RECT 1849.600000 16.320000 1852.960000 3323.840000 ;
        RECT 1876.800000 16.320000 1880.160000 3323.840000 ;
        RECT 1904.000000 16.320000 1907.360000 3323.840000 ;
        RECT 1931.200000 16.320000 1934.560000 3323.840000 ;
        RECT 1958.400000 16.320000 1961.760000 3323.840000 ;
        RECT 1985.600000 16.320000 1988.960000 3323.840000 ;
        RECT 2012.800000 16.320000 2016.160000 3323.840000 ;
        RECT 2040.000000 16.320000 2043.360000 3323.840000 ;
        RECT 2067.200000 16.320000 2070.560000 3323.840000 ;
        RECT 2094.400000 16.320000 2097.760000 3323.840000 ;
        RECT 2121.600000 16.320000 2124.960000 3323.840000 ;
        RECT 2148.800000 16.320000 2152.160000 3323.840000 ;
        RECT 2176.000000 16.320000 2179.360000 3323.840000 ;
        RECT 2203.200000 16.320000 2206.560000 3323.840000 ;
        RECT 2230.400000 16.320000 2233.760000 3323.840000 ;
        RECT 2257.600000 16.320000 2260.960000 3323.840000 ;
        RECT 2284.800000 16.320000 2288.160000 3323.840000 ;
        RECT 2312.000000 16.320000 2315.360000 3323.840000 ;
        RECT 2339.200000 16.320000 2342.560000 3323.840000 ;
        RECT 2366.400000 16.320000 2369.760000 3323.840000 ;
        RECT 2393.600000 16.320000 2396.960000 3323.840000 ;
        RECT 2420.800000 16.320000 2424.160000 3323.840000 ;
        RECT 2448.000000 16.320000 2451.360000 3323.840000 ;
        RECT 2475.200000 16.320000 2478.560000 3323.840000 ;
        RECT 2502.400000 16.320000 2505.760000 3323.840000 ;
        RECT 2529.600000 16.320000 2532.960000 3323.840000 ;
        RECT 2556.800000 16.320000 2560.160000 3323.840000 ;
        RECT 2584.000000 16.320000 2587.360000 3323.840000 ;
        RECT 2611.200000 16.320000 2614.560000 3323.840000 ;
        RECT 2638.400000 16.320000 2641.760000 3323.840000 ;
        RECT 2665.600000 16.320000 2668.960000 3323.840000 ;
        RECT 2692.800000 16.320000 2696.160000 3323.840000 ;
        RECT 2720.000000 16.320000 2723.360000 3323.840000 ;
        RECT 2747.200000 16.320000 2750.560000 3323.840000 ;
      LAYER met5 ;
        RECT 16.740000 27.200000 2770.400000 30.560000 ;
        RECT 0.000000 16.320000 2787.140000 24.480000 ;
        RECT 0.000000 3315.680000 2787.140000 3323.840000 ;
        RECT 16.740000 1142.400000 2770.400000 1145.760000 ;
        RECT 16.740000 1169.600000 2770.400000 1172.960000 ;
        RECT 16.740000 1196.800000 2770.400000 1200.160000 ;
        RECT 16.740000 1224.000000 2770.400000 1227.360000 ;
        RECT 16.740000 1251.200000 2770.400000 1254.560000 ;
        RECT 16.740000 1278.400000 2770.400000 1281.760000 ;
        RECT 16.740000 1305.600000 2770.400000 1308.960000 ;
        RECT 16.740000 1332.800000 2770.400000 1336.160000 ;
        RECT 16.740000 1360.000000 2770.400000 1363.360000 ;
        RECT 16.740000 1387.200000 2770.400000 1390.560000 ;
        RECT 16.740000 1414.400000 2770.400000 1417.760000 ;
        RECT 16.740000 1441.600000 2770.400000 1444.960000 ;
        RECT 16.740000 1468.800000 2770.400000 1472.160000 ;
        RECT 16.740000 1496.000000 2770.400000 1499.360000 ;
        RECT 16.740000 1523.200000 2770.400000 1526.560000 ;
        RECT 16.740000 1550.400000 2770.400000 1553.760000 ;
        RECT 16.740000 1577.600000 2770.400000 1580.960000 ;
        RECT 16.740000 1604.800000 2770.400000 1608.160000 ;
        RECT 16.740000 1632.000000 2770.400000 1635.360000 ;
        RECT 16.740000 1659.200000 2770.400000 1662.560000 ;
        RECT 16.740000 1686.400000 2770.400000 1689.760000 ;
        RECT 16.740000 1713.600000 2770.400000 1716.960000 ;
        RECT 16.740000 1740.800000 2770.400000 1744.160000 ;
        RECT 16.740000 1768.000000 2770.400000 1771.360000 ;
        RECT 16.740000 1795.200000 2770.400000 1798.560000 ;
        RECT 16.740000 1822.400000 2770.400000 1825.760000 ;
        RECT 16.740000 1849.600000 2770.400000 1852.960000 ;
        RECT 16.740000 1876.800000 2770.400000 1880.160000 ;
        RECT 16.740000 1904.000000 2770.400000 1907.360000 ;
        RECT 16.740000 1931.200000 2770.400000 1934.560000 ;
        RECT 16.740000 1958.400000 2770.400000 1961.760000 ;
        RECT 16.740000 1985.600000 2770.400000 1988.960000 ;
        RECT 16.740000 2012.800000 2770.400000 2016.160000 ;
        RECT 16.740000 2040.000000 2770.400000 2043.360000 ;
        RECT 16.740000 2067.200000 2770.400000 2070.560000 ;
        RECT 16.740000 2094.400000 2770.400000 2097.760000 ;
        RECT 16.740000 2121.600000 2770.400000 2124.960000 ;
        RECT 16.740000 2148.800000 2770.400000 2152.160000 ;
        RECT 16.740000 2176.000000 2770.400000 2179.360000 ;
        RECT 16.740000 2203.200000 2770.400000 2206.560000 ;
        RECT 16.740000 2230.400000 2770.400000 2233.760000 ;
        RECT 16.740000 2257.600000 2770.400000 2260.960000 ;
        RECT 16.740000 2284.800000 2770.400000 2288.160000 ;
        RECT 16.740000 2312.000000 2770.400000 2315.360000 ;
        RECT 16.740000 2339.200000 2770.400000 2342.560000 ;
        RECT 16.740000 2366.400000 2770.400000 2369.760000 ;
        RECT 16.740000 2393.600000 2770.400000 2396.960000 ;
        RECT 16.740000 2420.800000 2770.400000 2424.160000 ;
        RECT 16.740000 2448.000000 2770.400000 2451.360000 ;
        RECT 16.740000 2475.200000 2770.400000 2478.560000 ;
        RECT 16.740000 2502.400000 2770.400000 2505.760000 ;
        RECT 16.740000 2529.600000 2770.400000 2532.960000 ;
        RECT 16.740000 2556.800000 2770.400000 2560.160000 ;
        RECT 16.740000 2584.000000 2770.400000 2587.360000 ;
        RECT 16.740000 2611.200000 2770.400000 2614.560000 ;
        RECT 16.740000 2638.400000 2770.400000 2641.760000 ;
        RECT 16.740000 2665.600000 2770.400000 2668.960000 ;
        RECT 16.740000 2692.800000 2770.400000 2696.160000 ;
        RECT 16.740000 2720.000000 2770.400000 2723.360000 ;
        RECT 16.740000 2747.200000 2770.400000 2750.560000 ;
        RECT 16.740000 2774.400000 2770.400000 2777.760000 ;
        RECT 16.740000 2801.600000 2770.400000 2804.960000 ;
        RECT 16.740000 2828.800000 2770.400000 2832.160000 ;
        RECT 16.740000 2856.000000 2770.400000 2859.360000 ;
        RECT 16.740000 2883.200000 2770.400000 2886.560000 ;
        RECT 16.740000 2910.400000 2770.400000 2913.760000 ;
        RECT 16.740000 2937.600000 2770.400000 2940.960000 ;
        RECT 16.740000 2964.800000 2770.400000 2968.160000 ;
        RECT 16.740000 2992.000000 2770.400000 2995.360000 ;
        RECT 16.740000 3019.200000 2770.400000 3022.560000 ;
        RECT 16.740000 3046.400000 2770.400000 3049.760000 ;
        RECT 16.740000 3073.600000 2770.400000 3076.960000 ;
        RECT 16.740000 3100.800000 2770.400000 3104.160000 ;
        RECT 16.740000 3128.000000 2770.400000 3131.360000 ;
        RECT 16.740000 3155.200000 2770.400000 3158.560000 ;
        RECT 16.740000 3182.400000 2770.400000 3185.760000 ;
        RECT 16.740000 3209.600000 2770.400000 3212.960000 ;
        RECT 16.740000 3236.800000 2770.400000 3240.160000 ;
        RECT 16.740000 3264.000000 2770.400000 3267.360000 ;
        RECT 16.740000 3291.200000 2770.400000 3294.560000 ;
        RECT 16.740000 54.400000 2770.400000 57.760000 ;
        RECT 16.740000 81.600000 2770.400000 84.960000 ;
        RECT 16.740000 108.800000 2770.400000 112.160000 ;
        RECT 16.740000 136.000000 2770.400000 139.360000 ;
        RECT 16.740000 163.200000 2770.400000 166.560000 ;
        RECT 16.740000 190.400000 2770.400000 193.760000 ;
        RECT 16.740000 217.600000 2770.400000 220.960000 ;
        RECT 16.740000 244.800000 2770.400000 248.160000 ;
        RECT 16.740000 272.000000 2770.400000 275.360000 ;
        RECT 16.740000 299.200000 2770.400000 302.560000 ;
        RECT 16.740000 326.400000 2770.400000 329.760000 ;
        RECT 16.740000 353.600000 2770.400000 356.960000 ;
        RECT 16.740000 380.800000 2770.400000 384.160000 ;
        RECT 16.740000 408.000000 2770.400000 411.360000 ;
        RECT 16.740000 435.200000 2770.400000 438.560000 ;
        RECT 16.740000 462.400000 2770.400000 465.760000 ;
        RECT 16.740000 489.600000 2770.400000 492.960000 ;
        RECT 16.740000 516.800000 2770.400000 520.160000 ;
        RECT 16.740000 544.000000 2770.400000 547.360000 ;
        RECT 16.740000 571.200000 2770.400000 574.560000 ;
        RECT 16.740000 598.400000 2770.400000 601.760000 ;
        RECT 16.740000 625.600000 2770.400000 628.960000 ;
        RECT 16.740000 652.800000 2770.400000 656.160000 ;
        RECT 16.740000 680.000000 2770.400000 683.360000 ;
        RECT 16.740000 707.200000 2770.400000 710.560000 ;
        RECT 16.740000 734.400000 2770.400000 737.760000 ;
        RECT 16.740000 761.600000 2770.400000 764.960000 ;
        RECT 16.740000 788.800000 2770.400000 792.160000 ;
        RECT 16.740000 816.000000 2770.400000 819.360000 ;
        RECT 16.740000 843.200000 2770.400000 846.560000 ;
        RECT 16.740000 870.400000 2770.400000 873.760000 ;
        RECT 16.740000 897.600000 2770.400000 900.960000 ;
        RECT 16.740000 924.800000 2770.400000 928.160000 ;
        RECT 16.740000 952.000000 2770.400000 955.360000 ;
        RECT 16.740000 979.200000 2770.400000 982.560000 ;
        RECT 16.740000 1006.400000 2770.400000 1009.760000 ;
        RECT 16.740000 1033.600000 2770.400000 1036.960000 ;
    END
# end of P/G power stripe data as pin

  END VDD
  OBS
    LAYER li1 ;
      RECT 0.000000 0.000000 2787.140000 3340.160000 ;
    LAYER met1 ;
      RECT 0.000000 0.000000 2787.140000 3340.160000 ;
    LAYER met2 ;
      RECT 0.000000 0.000000 2787.140000 3340.160000 ;
    LAYER met3 ;
      RECT 0.000000 0.000000 2787.140000 3340.160000 ;
    LAYER met4 ;
      RECT 0.000000 0.000000 2787.140000 3340.160000 ;
    LAYER met5 ;
      RECT 0.000000 0.000000 2787.140000 3340.160000 ;
  END
END Pathtracer

END LIBRARY
